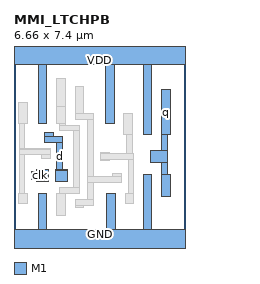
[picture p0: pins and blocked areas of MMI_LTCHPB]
MACRO MMI_LTCHPB
	CLASS CORE ;
	FOREIGN MMI_LTCHPB 0 0 ;
	SIZE 6.66 BY 7.4 ;
	SYMMETRY X Y ;
	SITE CORE1 ;
	PIN d
		DIRECTION input ;
		USE SIGNAL ;
		PORT
			LAYER M1 ;
			RECT 1.18 4.095 1.52 4.275 ;
			LAYER M1 ;
			RECT 1.18 3.865 1.89 4.095 ;
			LAYER M1 ;
			RECT 1.66 2.81 1.89 3.865 ;
			LAYER M1 ;
			RECT 1.62 2.8 2.075 2.81 ;
			LAYER M1 ;
			RECT 1.6 2.36 2.075 2.8 ;
		END
		AntennaGateArea 0.4968 ;
	END d
	PIN GND
		DIRECTION inout ;
		USE GROUND ;
		PORT
			LAYER M1 ;
			RECT 0.94 0.5 1.28 1.875 ;
			LAYER M1 ;
			RECT 3.61 0.5 3.95 1.875 ;
			LAYER M1 ;
			RECT 5.03 0.5 5.37 2.62 ;
			LAYER M1 ;
			RECT 0 -0.5 6.66 0.5 ;
		END
	END GND
	PIN q
		DIRECTION output ;
		USE SIGNAL ;
		PORT
			LAYER M1 ;
			RECT 5.75 4.18 6.09 5.94 ;
			LAYER M1 ;
			RECT 5.75 3.555 5.98 4.18 ;
			LAYER M1 ;
			RECT 5.325 3.105 5.98 3.555 ;
			LAYER M1 ;
			RECT 5.75 2.62 5.98 3.105 ;
			LAYER M1 ;
			RECT 5.75 1.78 6.09 2.62 ;
		END
		AntennaDiffArea 1.3248 ;
	END q
	PIN VDD
		DIRECTION inout ;
		USE POWER ;
		PORT
			LAYER M1 ;
			RECT 0 6.9 6.66 7.9 ;
			LAYER M1 ;
			RECT 0.94 4.605 1.28 6.9 ;
			LAYER M1 ;
			RECT 3.57 4.605 3.91 6.9 ;
			LAYER M1 ;
			RECT 5.03 4.18 5.37 6.9 ;
		END
	END VDD
	PIN clk
		DIRECTION input ;
		USE CLOCK ;
		PORT
			LAYER M1 ;
			RECT 1.026 2.81 1.335 2.812 ;
			LAYER M1 ;
			RECT 0.88 2.755 1.335 2.81 ;
			LAYER M1 ;
			RECT 0.685 2.415 1.335 2.755 ;
			LAYER M1 ;
			RECT 0.875 2.365 1.335 2.415 ;
			LAYER M1 ;
			RECT 0.876 2.364 1.335 2.365 ;
		END
		AntennaGateArea 0.4896 ;
	END clk
	OBS
		LAYER M1 ;
		RECT 0.18 4.605 0.52 5.445 ;
		LAYER M1 ;
		RECT 1.66 5.29 2 6.365 ;
		LAYER M1 ;
		RECT 1.66 4.605 2.01 5.29 ;
		LAYER M1 ;
		RECT 2.38 5.015 2.72 6.065 ;
		LAYER M1 ;
		RECT 2.38 4.785 3.1 5.015 ;
		LAYER M1 ;
		RECT 0.195 3.635 0.425 4.605 ;
		LAYER M1 ;
		RECT 1.78 4.555 2.01 4.605 ;
		LAYER M1 ;
		RECT 1.78 4.325 2.535 4.555 ;
		LAYER M1 ;
		RECT 0.195 3.605 1.428 3.635 ;
		LAYER M1 ;
		RECT 0.195 3.405 1.43 3.605 ;
		LAYER M1 ;
		RECT 0.195 1.875 0.425 3.405 ;
		LAYER M1 ;
		RECT 1.09 3.265 1.43 3.405 ;
		LAYER M1 ;
		RECT 2.305 2.13 2.535 4.325 ;
		LAYER M1 ;
		RECT 1.77 1.9 2.535 2.13 ;
		LAYER M1 ;
		RECT 2.87 2.545 3.1 4.785 ;
		LAYER M1 ;
		RECT 4.27 4.18 4.61 5.02 ;
		LAYER M1 ;
		RECT 3.37 3.445 3.71 3.495 ;
		LAYER M1 ;
		RECT 4.38 3.445 4.61 4.18 ;
		LAYER M1 ;
		RECT 3.37 3.215 4.67 3.445 ;
		LAYER M1 ;
		RECT 3.37 3.155 3.71 3.215 ;
		LAYER M1 ;
		RECT 3.85 2.545 4.19 2.655 ;
		LAYER M1 ;
		RECT 2.87 2.315 4.19 2.545 ;
		LAYER M1 ;
		RECT 1.77 1.875 2 1.9 ;
		LAYER M1 ;
		RECT 0.18 1.495 0.52 1.875 ;
		LAYER M1 ;
		RECT 1.66 1.035 2 1.875 ;
		LAYER M1 ;
		RECT 2.87 1.67 3.1 2.315 ;
		LAYER M1 ;
		RECT 4.44 1.875 4.67 3.215 ;
		LAYER M1 ;
		RECT 2.38 1.44 3.1 1.67 ;
		LAYER M1 ;
		RECT 2.38 1.33 2.72 1.44 ;
		LAYER M1 ;
		RECT 4.33 1.495 4.67 1.875 ;
		LAYER M1 ;
		RECT 4.44 1.494 4.67 1.495 ;
	END
END MMI_LTCHPB
